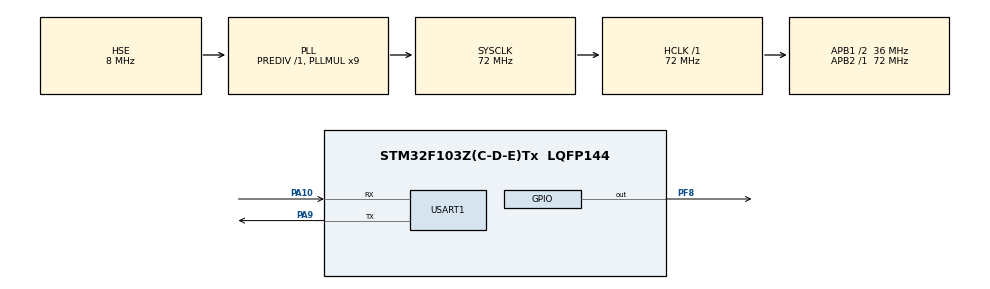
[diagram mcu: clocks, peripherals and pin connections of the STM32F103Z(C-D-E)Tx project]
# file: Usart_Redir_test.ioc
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Mcu.Family=STM32F1
Mcu.Name=STM32F103Z(C-D-E)Tx
Mcu.Package=LQFP144
NVIC.PriorityGroup=NVIC_PRIORITYGROUP_4
OSC_IN.Mode=HSE-External-Oscillator
OSC_IN.Signal=RCC_OSC_IN
OSC_OUT.Mode=HSE-External-Oscillator
OSC_OUT.Signal=RCC_OSC_OUT
PA10.Mode=Asynchronous
PA10.Signal=USART1_RX
PA13.Mode=Serial_Wire
PA13.Signal=SYS_JTMS-SWDIO
PA14.Mode=Serial_Wire
PA14.Signal=SYS_JTCK-SWCLK
PA9.Mode=Asynchronous
PA9.Signal=USART1_TX
PF8.PinState=GPIO_PIN_SET
PF8.Signal=GPIO_Output
ProjectManager.HeapSize=0x200
ProjectManager.StackSize=0x400
ProjectManager.TargetToolchain=MDK-ARM V5.32
RCC.AHBFreq_Value=72000000
RCC.APB1CLKDivider=RCC_HCLK_DIV2
RCC.APB1Freq_Value=36000000
RCC.APB1TimFreq_Value=72000000
RCC.APB2Freq_Value=72000000
RCC.APB2TimFreq_Value=72000000
RCC.HCLKFreq_Value=72000000
RCC.PLLMUL=RCC_PLL_MUL9
RCC.PLLSourceVirtual=RCC_PLLSOURCE_HSE
RCC.SYSCLKFreq_VALUE=72000000
RCC.SYSCLKSource=RCC_SYSCLKSOURCE_PLLCLK
RCC.USBFreq_Value=72000000
USART1.Parity=PARITY_ODD
USART1.VirtualMode=VM_ASYNC
USART1.WordLength=WORDLENGTH_9B
board=custom

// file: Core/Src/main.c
/* USER CODE BEGIN Header */
/**
 ******************************************************************************
 * @file           : main.c
 * @brief          : Main program body
 ******************************************************************************
 * @attention
 *
 * Copyright (c) 2026 STMicroelectronics.
 * All rights reserved.
 *
 * This software is licensed under terms that can be found in the LICENSE file
 * in the root directory of this software component.
 * If no LICENSE file comes with this software, it is provided AS-IS.
 *
 ******************************************************************************
 */
/* USER CODE END Header */
#include "main.h"

/* USER CODE BEGIN Includes */

#include "BSP_Usart_Redir.h"
#include "BSP_LED.h"
/* USER CODE END Includes */

UART_HandleTypeDef huart1;

/* USER CODE BEGIN PV */
char who[32]; // 全局空间缓冲�?保存要点亮的�?
/* USER CODE END PV */

void SystemClock_Config(void);
static void MX_GPIO_Init(void);
static void MX_USART1_UART_Init(void);
/* USER CODE BEGIN PFP */
void Usart_Ctl_LED();

/* USER CODE END PFP */

int main(void)
{

  /* MCU Configuration--------------------------------------------------------*/

  /* Reset of all peripherals, Initializes the Flash interface and the Systick. */
  HAL_Init();

  /* Configure the system clock */
  SystemClock_Config();

  /* Initialize all configured peripherals */
  MX_GPIO_Init();
  MX_USART1_UART_Init();
  /* USER CODE BEGIN 2 */
  BSP_Usart_Init(&huart1);
  char inbuffer[32];
  printf("Test begin...");

  /* USER CODE END 2 */

  /* Infinite loop */
  /* USER CODE BEGIN WHILE */
  while (1)
  {
    Usart_Ctl_LED();
    // v3
    // fgets(inbuffer, 31, stdin);
    // int a = 0;
    // scanf("%d", &a);
    // printf("echo->%d\n", a);
    // BSP_Led_On(LED1);

    // // v2
    // int a=0;
    // scanf("%d",&a);
    // //fgets(inbuffer, 31, stdin);
    // printf("echo->%d\n", a);

    // HAL_GPIO_TogglePin(GPIOF, GPIO_PIN_8);
    // v1
    //  printf("hello : %d,hello %.2f,hello: %s", 111, 3.14, "STM32F103");
    //  HAL_GPIO_TogglePin(GPIOF, GPIO_PIN_8);
    //  HAL_Delay(1000);
    /* USER CODE END WHILE */

  }
}

void SystemClock_Config(void)
{
  RCC_OscInitTypeDef RCC_OscInitStruct = {0};
  RCC_ClkInitTypeDef RCC_ClkInitStruct = {0};

  /** Initializes the RCC Oscillators according to the specified parameters
  * in the RCC_OscInitTypeDef structure.
  */
  RCC_OscInitStruct.OscillatorType = RCC_OSCILLATORTYPE_HSE;
  RCC_OscInitStruct.HSEState = RCC_HSE_ON;
  RCC_OscInitStruct.HSEPredivValue = RCC_HSE_PREDIV_DIV1;
  RCC_OscInitStruct.HSIState = RCC_HSI_ON;
  RCC_OscInitStruct.PLL.PLLState = RCC_PLL_ON;
  RCC_OscInitStruct.PLL.PLLSource = RCC_PLLSOURCE_HSE;
  RCC_OscInitStruct.PLL.PLLMUL = RCC_PLL_MUL9;
  if (HAL_RCC_OscConfig(&RCC_OscInitStruct) != HAL_OK)
  {
    Error_Handler();
  }

  /** Initializes the CPU, AHB and APB buses clocks
  */
  RCC_ClkInitStruct.ClockType = RCC_CLOCKTYPE_HCLK|RCC_CLOCKTYPE_SYSCLK
                              |RCC_CLOCKTYPE_PCLK1|RCC_CLOCKTYPE_PCLK2;
  RCC_ClkInitStruct.SYSCLKSource = RCC_SYSCLKSOURCE_PLLCLK;
  RCC_ClkInitStruct.AHBCLKDivider = RCC_SYSCLK_DIV1;
  RCC_ClkInitStruct.APB1CLKDivider = RCC_HCLK_DIV2;
  RCC_ClkInitStruct.APB2CLKDivider = RCC_HCLK_DIV1;

  if (HAL_RCC_ClockConfig(&RCC_ClkInitStruct, FLASH_LATENCY_2) != HAL_OK)
  {
    Error_Handler();
  }
}

static void MX_USART1_UART_Init(void)
{

  huart1.Instance = USART1;
  huart1.Init.BaudRate = 115200;
  huart1.Init.WordLength = UART_WORDLENGTH_9B;
  huart1.Init.StopBits = UART_STOPBITS_1;
  huart1.Init.Parity = UART_PARITY_ODD;
  huart1.Init.Mode = UART_MODE_TX_RX;
  huart1.Init.HwFlowCtl = UART_HWCONTROL_NONE;
  huart1.Init.OverSampling = UART_OVERSAMPLING_16;
  if (HAL_UART_Init(&huart1) != HAL_OK)
  {
    Error_Handler();
  }

}

static void MX_GPIO_Init(void)
{
  GPIO_InitTypeDef GPIO_InitStruct = {0};

  /* GPIO Ports Clock Enable */
  __HAL_RCC_GPIOF_CLK_ENABLE();
  __HAL_RCC_GPIOA_CLK_ENABLE();

  /*Configure GPIO pin Output Level */
  HAL_GPIO_WritePin(GPIOF, GPIO_PIN_8|GPIO_PIN_9|GPIO_PIN_10|GPIO_PIN_11, GPIO_PIN_SET);

  /*Configure GPIO pins : PF8 PF9 PF10 PF11 */
  GPIO_InitStruct.Pin = GPIO_PIN_8|GPIO_PIN_9|GPIO_PIN_10|GPIO_PIN_11;
  GPIO_InitStruct.Mode = GPIO_MODE_OUTPUT_PP;
  GPIO_InitStruct.Pull = GPIO_NOPULL;
  GPIO_InitStruct.Speed = GPIO_SPEED_FREQ_LOW;
  HAL_GPIO_Init(GPIOF, &GPIO_InitStruct);

}

/* USER CODE BEGIN 4 */

void Usart_Ctl_LED()
{
  int SIZE = 33;
  fgets(who, SIZE - 1, stdin);
  if (strncasecmp(who, "LED1", strlen("LED1")) == 0)
  {
    printf("LED1 开始闪烁...\n");
    LED_Link(LED1);
  }
  if (strncasecmp(who, "LED2", strlen("LED2")) == 0)
  {
    printf("LED2 开始闪烁...\n");
    LED_Link(LED2);
  }
  if (strncasecmp(who, "LED3", strlen("LED3")) == 0)
  {
    printf("LED3 开始闪烁...\n");
    LED_Link(LED3);
  }
  if (strncasecmp(who, "LED4", strlen("LED4")) == 0)
  {
    printf("LED4 开始闪烁...\n");
    LED_Link(LED4);
  }
  if (strncasecmp(who, "ALL", strlen("ALL")) == 0)
  {
    printf("LED1|2|3|4 开始闪烁...\n");

    LED_Link(ALL);
  }
}

// int fputc(int ch, FILE *fp)
// {
//   UNUSED(fp);

//   if (HAL_UART_Transmit(&huart1, (uint8_t *)&ch, 1, HAL_MAX_DELAY) == HAL_OK)
//   {
//     return ch;
//   }
//   return EOF;
// }

// int fgetc(FILE *fp)
// {
//   UNUSED(fp);
//   static uint8_t last_was_cr = 0;
//   uint8_t ch;

//   while (1)
//   {
//     if (HAL_UART_Receive(&huart1, &ch, 1, HAL_MAX_DELAY) != HAL_OK)
//     {
//       return EOF;
//     }

//     if (last_was_cr)
//     {
//       last_was_cr = 0;
//       if (ch == '\n')
//       {
//         continue;
//       }
//     }

//     if (ch == '\r')
//     {
//       last_was_cr = 1;
//       return '\n';
//     }

//     return (int)ch;
//   }
// }
/* USER CODE END 4 */

void Error_Handler(void)
{
  __disable_irq();
  while (1)
  {
  }
}
